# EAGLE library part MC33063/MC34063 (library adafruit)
MC33063 and MC34063 Basic DC/DC converter with internal power-NPN transistor, 100KHz, 1.5A peak switch current. 3-40 input/output.

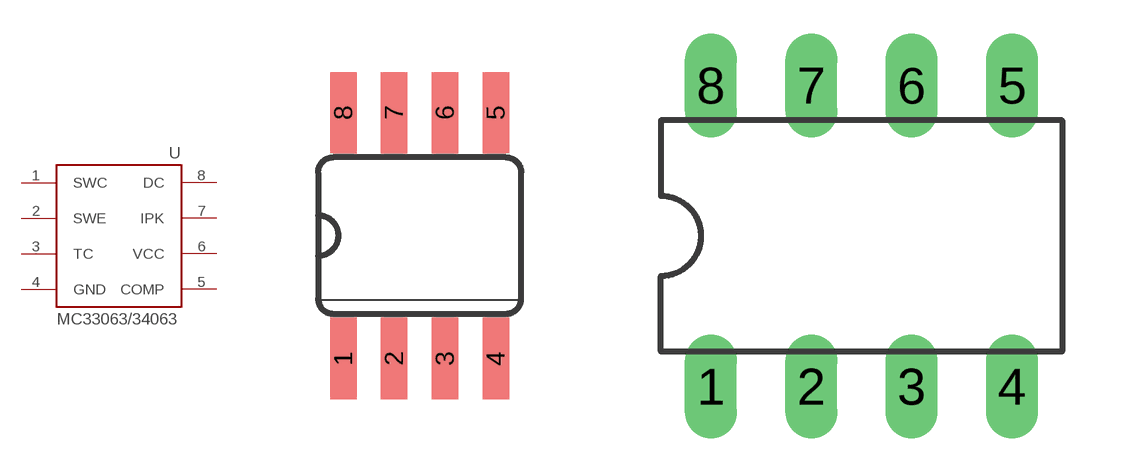
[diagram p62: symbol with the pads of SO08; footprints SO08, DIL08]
Designator prefix -

## MC33063/MC34063D  [SO08]
1  SWC  in
2  SWE  in
3  TC  in
4  GND  pwr
5  COMP  in
6  VCC  pwr
7  IPK
8  DC  in

## MC33063/MC34063P  [DIL08]
Pads as for SO08

## Footprint SO08 (pad centres in mm)
smd 0.66 x 2.032: 1 -1.905,-3.073; 2 -0.635,-3.073; 3 0.635,-3.073; 4 1.905,-3.073; 5 1.905,3.073; 6 0.635,3.073; 7 -0.635,3.073; 8 -1.905,3.073

## Footprint DIL08 (pad centres in mm)
Dual In Line Package
drill 0.813 long: 1 -3.81,-3.81; 2 -1.27,-3.81; 3 1.27,-3.81; 4 3.81,-3.81; 5 3.81,3.81; 6 1.27,3.81; 7 -1.27,3.81; 8 -3.81,3.81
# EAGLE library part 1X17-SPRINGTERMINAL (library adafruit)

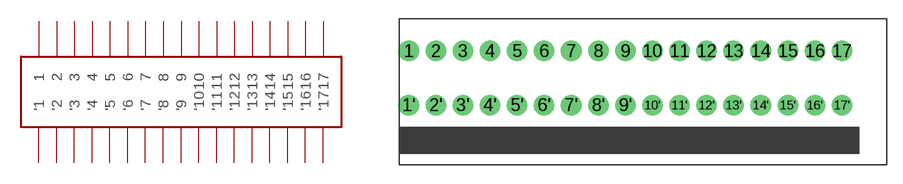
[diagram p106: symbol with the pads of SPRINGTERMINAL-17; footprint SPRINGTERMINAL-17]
Designator prefix Q

## 1X17-SPRINGTERMINAL  [SPRINGTERMINAL-17]
1  1  pas
1'  '1  pas
2  2  pas
2'  '2  pas
3  3  pas
3'  '3  pas
4  4  pas
4'  '4  pas
5  5  pas
5'  '5  pas
6  6  pas
6'  '6  pas
7  7  pas
7'  '7  pas
8  8  pas
8'  '8  pas
9  9  pas
9'  '9  pas
10  10  pas
10'  '10  pas
11  11  pas
11'  '11  pas
12  12  pas
12'  '12  pas
13  13  pas
13'  '13  pas
14  14  pas
14'  '14  pas
15  15  pas
15'  '15  pas
16  16  pas
16'  '16  pas
17  17  pas
17'  '17  pas

## Footprint SPRINGTERMINAL-17 (pad centres in mm)
drill 1.1 pad 1.93: 1 -20.32,5.08; 1' -20.32,0; 2 -17.78,5.08; 2' -17.78,0; 3 -15.24,5.08; 3' -15.24,0; 4 -12.7,5.08; 4' -12.7,0; 5 -10.16,5.08; 5' -10.16,0; 6 -7.62,5.08; 6' -7.62,0; 7 -5.08,5.08; 7' -5.08,0; 8 -2.54,5.08; 8' -2.54,0; 9 0,5.08; 9' 0,0; 10 2.54,5.08; 10' 2.54,0; 11 5.08,5.08; 11' 5.08,0; 12 7.62,5.08; 12' 7.62,0; 13 10.16,5.08; 13' 10.16,0; 14 12.7,5.08; 14' 12.7,0; 15 15.24,5.08; 15' 15.24,0; 16 17.78,5.08; 16' 17.78,0; 17 20.32,5.08; 17' 20.32,0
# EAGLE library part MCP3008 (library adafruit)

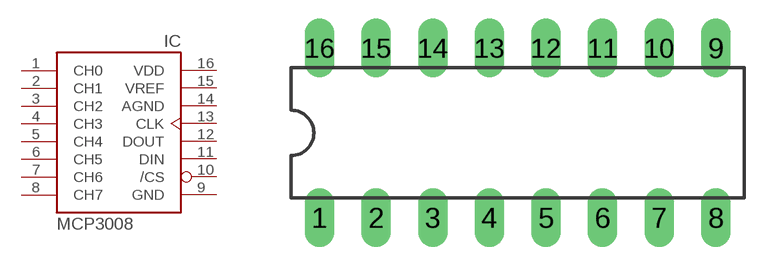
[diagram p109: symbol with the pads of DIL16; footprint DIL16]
Designator prefix IC

## MCP3008  [DIL16]
1  CH0  in
2  CH1  in
3  CH2  in
4  CH3  in
5  CH4  in
6  CH5  in
7  CH6  in
8  CH7  in
9  GND  pwr
10  /CS  in
11  DIN  in
12  DOUT  out
13  CLK  in
14  AGND  pwr
15  VREF  in
16  VDD  pwr

## Footprint DIL16 (pad centres in mm)
Dual In Line Package
drill 0.813 long: 1 -8.89,-3.81; 2 -6.35,-3.81; 3 -3.81,-3.81; 4 -1.27,-3.81; 5 1.27,-3.81; 6 3.81,-3.81; 7 6.35,-3.81; 8 8.89,-3.81; 9 8.89,3.81; 10 6.35,3.81; 11 3.81,3.81; 12 1.27,3.81; 13 -1.27,3.81; 14 -3.81,3.81; 15 -6.35,3.81; 16 -8.89,3.81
